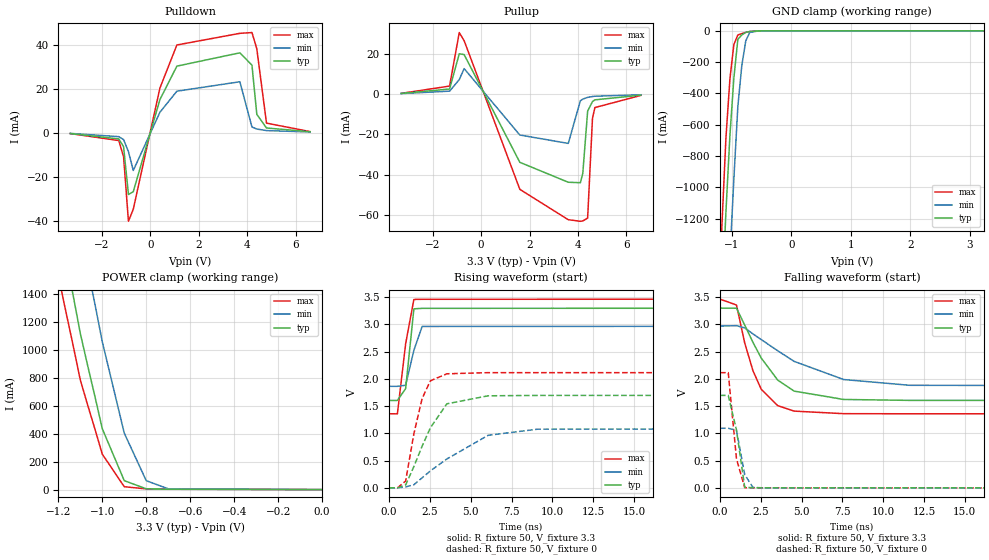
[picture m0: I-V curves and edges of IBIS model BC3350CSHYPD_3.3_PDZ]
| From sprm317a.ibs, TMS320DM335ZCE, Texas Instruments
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|   Model Cell BC3350CSHYPD_3.3_PDZ
[Model]   BC3350CSHYPD_3.3_PDZ
Model_type   I/O
Polarity   Non-Inverting
Enable   Active-Low
Vinl =  1.5
Vinh =  1.8
Cref =  15.0000pF
Rref =  100.0000M
Vref =  0V
Vmeas =  1.65
C_comp   0.972592p   0.9599789p   0.9808023p
[Model Spec]
Vinl   1.5   1.335   1.5825
Vinh   1.8   1.635   1.8825
[Temperature Range]   25   125   -40
[Voltage Range]   3.3   2.97   3.465
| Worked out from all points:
|   slope of the pulldown table from 0 to 0.495 V, typ, clamps not added: 27.7 ohm
|   slope of the pullup table from 0 to 0.495 V, typ, clamps not added: 37.2 ohm
|   GND clamp passes 1 mA (typ) near -0.58 V on its own axis
|   POWER clamp passes 1 mA (typ) near -0.55 V on its own axis
|   rising waveform, R_fixture 50, V_fixture 3.3: 20-80 % time 351ps typ, 604ps min, 587ps max; typ from 1.6 V to 3.3 V
|   rising waveform, R_fixture 50, V_fixture 0: 20-80 % time 1.55ns typ, 3.16ns min, 918ps max; typ from 0 V to 1.7 V
|   falling waveform, R_fixture 50, V_fixture 3.3: 20-80 % time 2.12ns typ, 3.91ns min, 1.37ns max; typ from 3.3 V to 1.6 V
|   falling waveform, R_fixture 50, V_fixture 0: 20-80 % time 583ps typ, 442ps min, 475ps max; typ from 1.7 V to 0 V
[POWER_clamp]
|   voltage   I(typ)   I(min)   I(max)
-3.3V     22.26A     22.97A     21.87A
-1.2V     1.947A     2.724A     1.536A
-1.167V   1.672A     2.436A     1.287A
-1.133V   1.397A     2.148A     1.037A
-1.1V     1.121A     1.86A      787mA
-1.067V   893.3mA    1.594A     609.5mA
-1.033V   665.1mA    1.327A     432mA
-1V       437mA      1.061A     254.4mA
-900mV    64.15mA    405.2mA    20.71mA
-800mV    5.778mA    63.92mA    5.206mA
-700mV    2.598mA    5.749mA    3.134mA
-11.55fV  463.7pA    9.257nA    235.3pA
[Pulldown]
|   voltage   I(typ)   I(min)   I(max)
-3.3V     -403.6uA   -328.8uA   -418.9uA
-1.3V     -2.841mA   -1.807mA   -3.581mA
-1.1V     -6.386mA   -3.145mA   -10.99mA
-900mV    -28.11mA   -8.625mA   -40.3mA
-700mV    -26.83mA   -17.2mA    -34.78mA
400mV     15.05mA    9.288mA    20.3mA
1.1V      30.25mA    18.85mA    39.86mA
3.7V      36.3mA     23.15mA    45.16mA
4.2V      30.68mA    2.555mA    45.51mA
4.4V      8.337mA    1.643mA    38.15mA
4.8V      2.127mA    941.5uA    4.342mA
6.6V      435.4uA    314uA      481.3uA
[Pullup]
|   voltage   I(typ)   I(min)   I(max)
-3.3V     327.4uA    259.3uA    367uA
-1.3V     2.541mA    1.473mA    3.993mA
-900mV    20.05mA    7.198mA    30.58mA
-700mV    19.65mA    12.69mA    26.57mA
1.6V      -33.88mA   -20.32mA   -47.31mA
3.6V      -43.79mA   -24.49mA   -62.4mA
4.1V      -44.01mA   -3.32mA    -63.19mA
4.2V      -39.34mA   -2.47mA    -63.02mA
4.4V      -8.445mA   -1.612mA   -61.59mA
4.6V      -3.699mA   -1.188mA   -11.99mA
4.7V      -2.851mA   -1.049mA   -6.683mA
6.6V      -510.5uA   -319.6uA   -632.9uA
[GND_clamp]
|   voltage   I(typ)   I(min)   I(max)
-3.3V     -22.38A    -23.15A    -21.96A
-1.167V   -1.724A    -2.574A    -1.236A
-1.1V     -1.155A    -1.991A    -683mA
-1.033V   -667.4mA   -1.447A    -306.3mA
-966.7mV  -300.7mA   -944.1mA   -87.49mA
-900mV    -54.69mA   -483.8mA   -26.44mA
-833.3mV  -26.36mA   -221.5mA   -17.65mA
-766.7mV  -9.653mA   -63.73mA   -10.3mA
-700mV    -4.567mA   -10.63mA   -4.402mA
-566.7mV  -685.9uA   -1.481mA   -426uA
-433.3mV  -37.32uA   -149uA     -13uA
3.233V    -355.1pA   12.26uA    155.1pA
[Ramp]
| variable   typ   min   max
dV/dt_f   1.028481/2.11349n   0.6724248/3.940643n   1.275888/1.372982n
dV/dt_r   1.018888/1.520105n   0.6566824/3.139877n   1.26944/0.9065815n
R_load = 50
[Rising Waveform]
R_fixture = 50
V_fixture = 3.3
V_fixture_min = 2.97
V_fixture_max = 3.465
| time   V(typ)   V(min)   V(max)
|   time   V(typ)   V(min)   V(max)
0s        1.605V     1.864V     1.36V
505.1ps   1.605V     1.864V     1.359V
1.01ns    1.822V     1.884V     2.646V
1.515ns   3.287V     2.526V     3.459V
2.02ns    3.296V     2.963V     3.462V
50ns      3.3V       2.97V      3.465V
[Rising Waveform]
R_fixture = 50
V_fixture = 0
V_fixture_min = 0
V_fixture_max = 0
| time   V(typ)   V(min)   V(max)
|   time   V(typ)   V(min)   V(max)
0s        57.87nV    467.1nV    5.382nV
505.1ps   -6.187uV   121.2nV    -261.8uV
1.01ns    52.77mV    17.12mV    124.8mV
1.515ns   391.3mV    56.51mV    994.7mV
2.02ns    765.2mV    185mV      1.64V
2.525ns   1.102V     311.3mV    1.965V
3.535ns   1.543V     530mV      2.094V
6.061ns   1.69V      964.4mV    2.115V
9.091ns   1.697V     1.077V     2.115V
50ns      1.698V     1.094V     2.115V
[Falling Waveform]
R_fixture = 50
V_fixture = 3.3
V_fixture_min = 2.97
V_fixture_max = 3.465
| time   V(typ)   V(min)   V(max)
|   time   V(typ)   V(min)   V(max)
0s        3.3V       2.97V      3.465V
1.01ns    3.298V     2.978V     3.357V
1.515ns   2.989V     2.937V     2.66V
2.02ns    2.671V     2.826V     2.151V
2.525ns   2.384V     2.723V     1.811V
3.535ns   1.979V     2.517V     1.51V
4.545ns   1.776V     2.322V     1.409V
7.576ns   1.623V     1.989V     1.362V
11.62ns   1.606V     1.883V     1.36V
50ns      1.605V     1.864V     1.36V
[Falling Waveform]
R_fixture = 50
V_fixture = 0
V_fixture_min = 0
V_fixture_max = 0
| time   V(typ)   V(min)   V(max)
|   time   V(typ)   V(min)   V(max)
0s        1.698V     1.094V     2.115V
505.1ps   1.698V     1.094V     2.115V
1.01ns    1.062V     1.057V     533.3mV
1.515ns   12.16mV    241.5mV    2.425mV
2.02ns    1.751mV    8.246mV    1.107mV
2.525ns   1.092mV    1.846mV    624.1uV
50ns      106.3nV    504.7nV    39.12nV
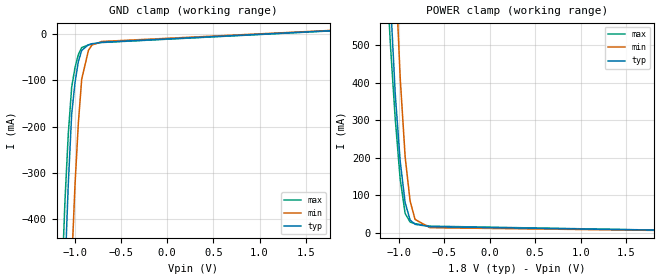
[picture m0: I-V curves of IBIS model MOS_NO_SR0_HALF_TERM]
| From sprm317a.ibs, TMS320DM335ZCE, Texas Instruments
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|   Model Cell MOS_NO_SR0_HALF_TERM
[Model]   MOS_NO_SR0_HALF_TERM
Model_type   Input
Polarity   Non-Inverting
Vinl =  0.80
Vinh =  1.00
C_comp   2.680301p   2.549919p   2.900942p
[Model Spec]
Vinl   0.80   0.71   0.89
Vinh   1.00   0.91   1.09
[Temperature Range]   25   125   -40
[Voltage Range]   1.8   1.62   1.89
[POWER_clamp]
|   voltage   I(typ)   I(min)   I(max)
-1.8V     6.874A     7.433A     6.581A
-1.127V   863.6mA    1.359A     685.7mA
-1.109V   748mA      1.221A     597.1mA
-1.091V   632.4mA    1.084A     508.6mA
-1.036V   370.1mA    715.2mA    303.8mA
-1.018V   310.4mA    614.7mA    250.4mA
-981.8mV  191mA      413.7mA    143.7mA
-927.3mV  80.54mA    202.5mA    51.79mA
-872.7mV  34.19mA    84.62mA    28.92mA
-818.2mV  22.98mA    35.89mA    24.65mA
-654.5mV  16.62mA    13.98mA    18.04mA
1.8V      7.556mA    6.792mA    7.728mA
[GND_clamp]
|   voltage   I(typ)   I(min)   I(max)
-1.8V     -6.676A    -7.172A    -6.432A
-1.145V   -748.7mA   -1.247A    -551.3mA
-1.109V   -517.9mA   -978.4mA   -362.4mA
-1.073V   -326mA     -728.7mA   -217mA
-1.036V   -173.2mA   -497.8mA   -115mA
-1V       -105.3mA   -326.4mA   -72.7mA
-963.6mV  -59.38mA   -192.9mA   -44.14mA
-927.3mV  -35.3mA    -97.41mA   -29.26mA
-854.5mV  -23.15mA   -35.57mA   -23.44mA
-818.2mV  -20.91mA   -23.96mA   -21.89mA
-709.1mV  -17.69mA   -15.96mA   -18.22mA
1.764V    7.278mA    7.846mA    6.783mA
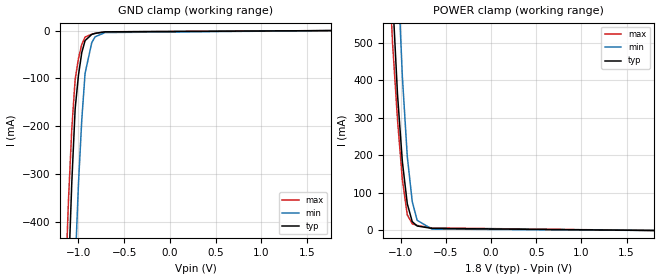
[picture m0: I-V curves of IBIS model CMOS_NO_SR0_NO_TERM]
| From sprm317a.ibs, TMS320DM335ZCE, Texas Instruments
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|   Model Cell CMOS_NO_SR0_NO_TERM
[Model]   CMOS_NO_SR0_NO_TERM
Model_type   Input
Polarity   Non-Inverting
Vinl =  0.80
Vinh =  1.00
C_comp   2.680301p   2.549919p   2.900942p
[Model Spec]
Vinl   0.80   0.71   0.89
Vinh   1.00   0.91   1.09
[Temperature Range]   25   125   -40
[Voltage Range]   1.8   1.62   1.89
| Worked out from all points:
|   GND clamp passes 1 mA (typ) near -0.61 V on its own axis
|   POWER clamp passes 1 mA (typ) near -0.44 V on its own axis
[POWER_clamp]
|   voltage   I(typ)   I(min)   I(max)
-1.8V     6.874A     7.433A     6.58A
-1.127V   860mA      1.357A     680.3mA
-1.109V   743.9mA    1.22A      591.2mA
-1.091V   627.9mA    1.082A     502.1mA
-1.036V   363.7mA    712.2mA    296.4mA
-1.018V   303.5mA    611.3mA    242.6mA
-981.8mV  183mA      409.6mA    135.2mA
-927.3mV  71.09mA    196.6mA    41.52mA
-872.7mV  23.54mA    77.04mA    17.73mA
-818.2mV  11.93mA    27.03mA    13.33mA
-654.5mV  5.543mA    3.815mA    6.744mA
1.8V      1.289nA    7.48nA     1.276nA
[GND_clamp]
|   voltage   I(typ)   I(min)   I(max)
-1.8V     -6.675A    -7.171A    -6.432A
-1.145V   -744.8mA   -1.245A    -545.6mA
-1.109V   -512.4mA   -975.9mA   -354.4mA
-1.073V   -318.5mA   -725.6mA   -206.5mA
-1.036V   -163.2mA   -493.8mA   -102mA
-1V       -93.34mA   -321.1mA   -58.49mA
-963.6mV  -45.91mA   -186.2mA   -29.01mA
-927.3mV  -20.88mA   -89.08mA   -13.53mA
-854.5mV  -8.057mA   -25.26mA   -7.542mA
-818.2mV  -5.73mA    -13.02mA   -6.017mA
-709.1mV  -2.662mA   -4.111mA   -2.579mA
1.764V    -1.607nA   1.693uA    1.056nA
